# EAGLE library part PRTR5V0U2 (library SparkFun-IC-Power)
A small ESD protection device. Most commonly used on USB D+/D- signals to protect large, expensive, or especially sensitive USB enabled devices.

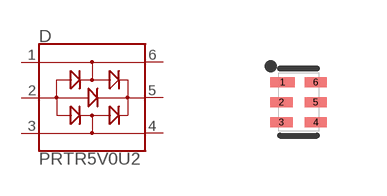
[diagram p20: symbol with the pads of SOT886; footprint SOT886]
Designator prefix D

## PRTR5V0U2F (PROD_ID: DIO-14084)  [SOT886]
1  1
2  2  pwr
3  3
4  4
5  5  pwr
6  6

## Footprint SOT886 (pad centres in mm)
SOT886 Package for "F" variant of PRTR5V0U2F
smd 0.61 x 0.25: 1 -0.405,0.5
smd 0.56 x 0.25: 2 -0.43,0; 3 -0.43,-0.5; 4 0.43,-0.5; 5 0.43,0; 6 0.43,0.5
